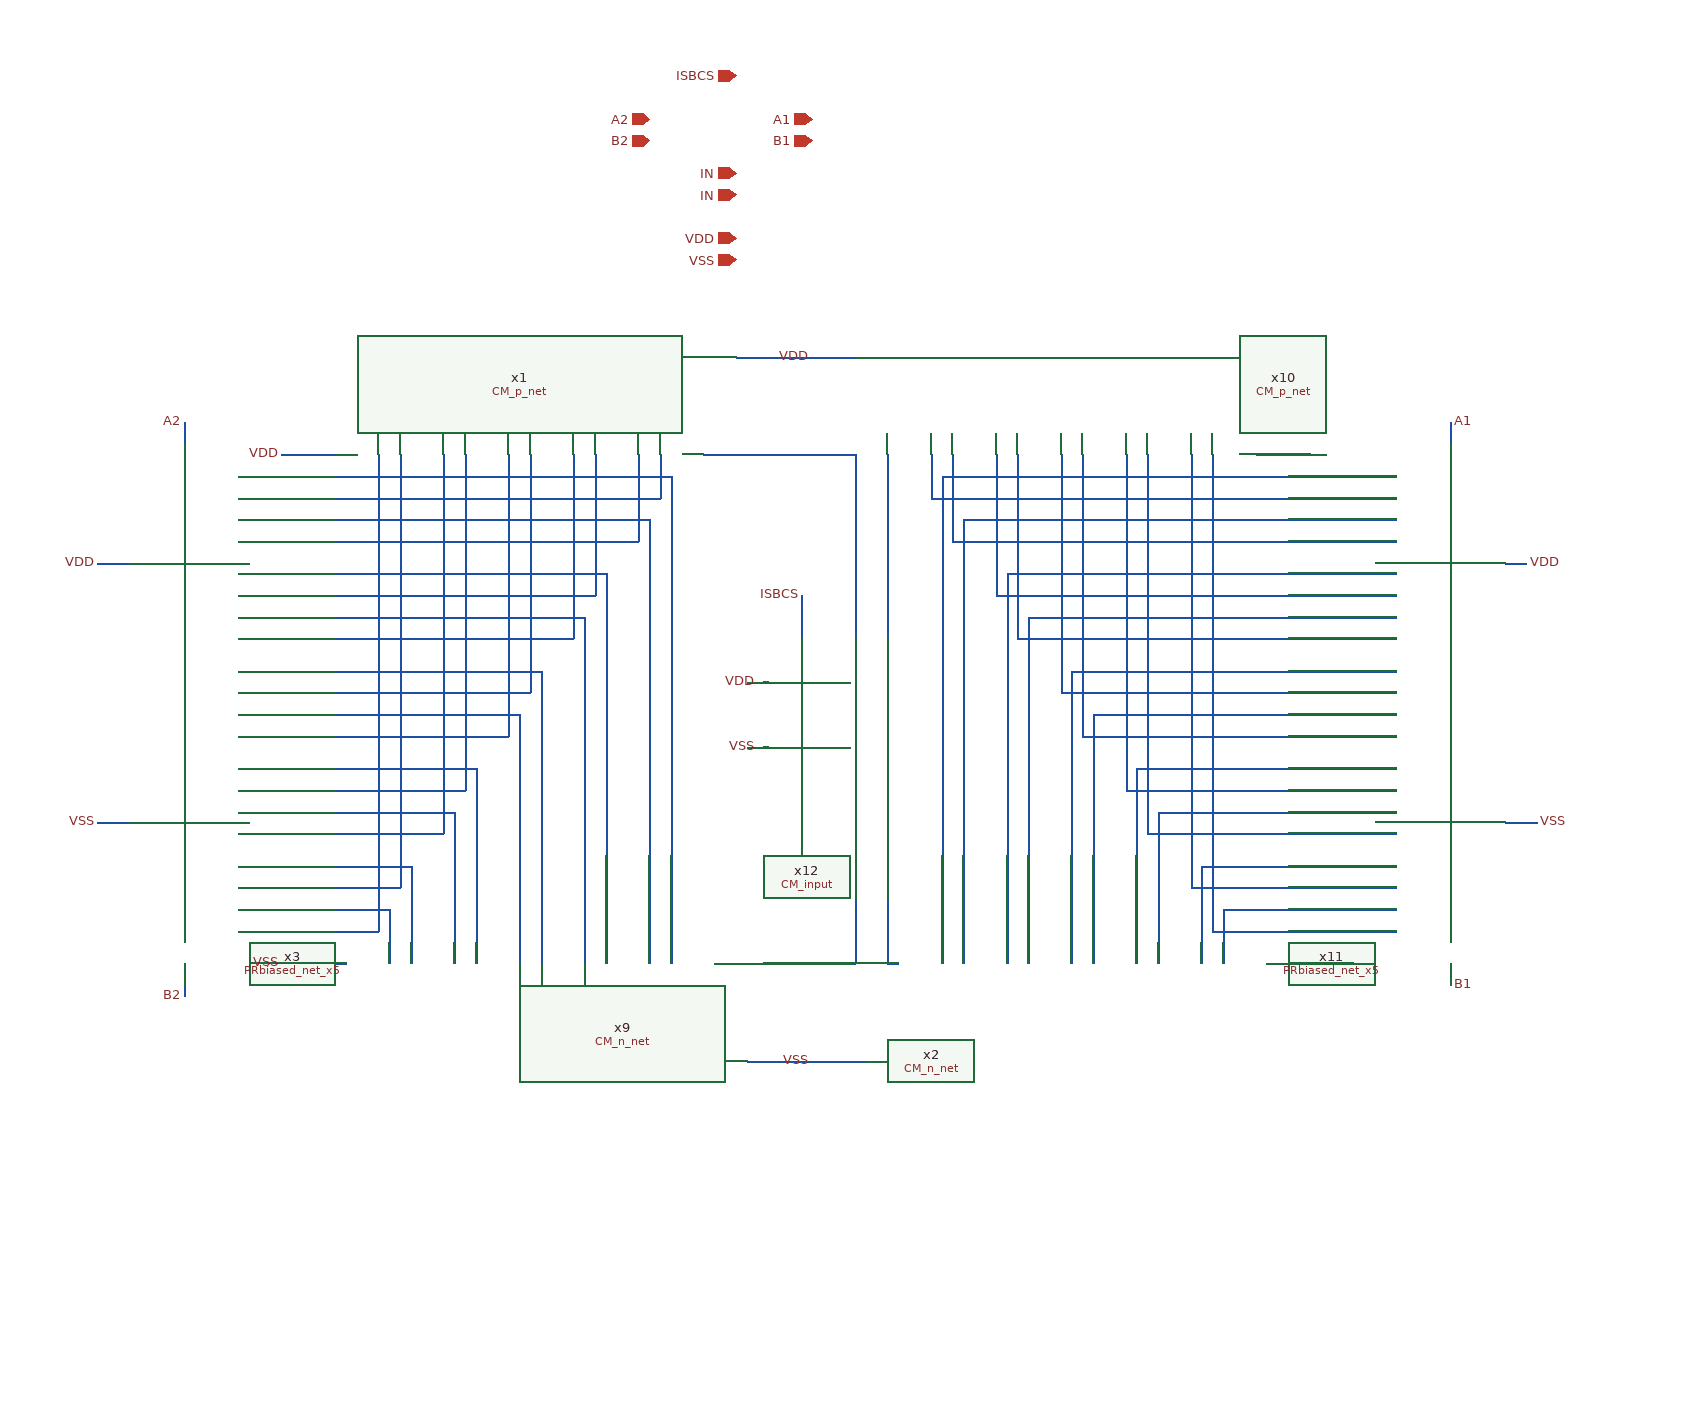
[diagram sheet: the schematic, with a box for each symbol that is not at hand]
v {xschem version=3.4.5 file_version=1.2
}
G {}
K {}
V {}
S {}
E {}
N 380 -390 380 -370 {
lab=#net1}
N 380 -310 380 -230 {
lab=#net1}
N 380 -560 380 -530 {
lab=#net2}
N 380 -700 380 -620 {
lab=#net2}
N 380 -230 390 -230 {
lab=#net1}
N 430 -680 850 -680 {
lab=#net3}
N 450 -640 850 -640 {
lab=#net4}
N 490 -590 850 -590 {
lab=#net5}
N 490 -590 490 -230 {
lab=#net5}
N 550 -500 850 -500 {
lab=#net6}
N 550 -500 550 -230 {
lab=#net6}
N 570 -460 570 -230 {
lab=#net7}
N 570 -460 850 -460 {
lab=#net7}
N 610 -410 850 -410 {
lab=#net8}
N 610 -410 610 -230 {
lab=#net8}
N 630 -370 850 -370 {
lab=#net9}
N 630 -370 630 -230 {
lab=#net9}
N 670 -320 670 -230 {
lab=#net10}
N 670 -320 850 -320 {
lab=#net10}
N 690 -280 850 -280 {
lab=#net11}
N 690 -280 690 -230 {
lab=#net11}
N 510 -550 850 -550 {
lab=#net12}
N 510 -520 510 -230 {
lab=#net12}
N 420 -660 850 -660 {
lab=#net13}
N 420 -700 420 -660 {
lab=#net13}
N 440 -620 850 -620 {
lab=#net14}
N 440 -700 440 -620 {
lab=#net14}
N 480 -570 850 -570 {
lab=#net15}
N 480 -700 480 -570 {
lab=#net15}
N 500 -530 850 -530 {
lab=#net16}
N 500 -700 500 -530 {
lab=#net16}
N 540 -480 850 -480 {
lab=#net17}
N 540 -700 540 -480 {
lab=#net17}
N 560 -440 850 -440 {
lab=#net18}
N 560 -700 560 -440 {
lab=#net18}
N 600 -390 850 -390 {
lab=#net19}
N 600 -700 600 -390 {
lab=#net19}
N 620 -350 850 -350 {
lab=#net20}
N 620 -700 620 -350 {
lab=#net20}
N 660 -300 850 -300 {
lab=#net21}
N 660 -700 660 -300 {
lab=#net21}
N 680 -260 850 -260 {
lab=#net22}
N 680 -700 680 -260 {
lab=#net22}
N 430 -680 430 -300 {
lab=#net3}
N 450 -640 450 -300 {
lab=#net4}
N 730 -230 810 -230 {
lab=#net23}
N 720 -700 770 -700 {
lab=#net24}
N 510 -550 510 -520 {
lab=#net12}
N 430 -300 430 -230 {
lab=#net3}
N 450 -300 450 -230 {
lab=#net4}
N 380 -370 380 -310 {
lab=#net1}
N 380 -620 380 -560 {
lab=#net2}
N 210 -700 350 -700 {
lab=#net25}
N 350 -700 350 -530 {
lab=#net25}
N 220 -230 350 -230 {
lab=#net26}
N 350 -390 350 -230 {
lab=#net26}
N 250 -140 360 -140 {
lab=VSS}
N 240 -790 350 -790 {
lab=VDD}
N -180 -230 -120 -230 {
lab=VSS}
N 180 -680 180 -230 {
lab=#net27}
N 160 -640 160 -230 {
lab=#net28}
N -220 -640 160 -640 {
lab=#net28}
N -220 -590 120 -590 {
lab=#net29}
N 120 -590 120 -230 {
lab=#net29}
N 100 -550 100 -230 {
lab=#net30}
N -220 -550 100 -550 {
lab=#net30}
N -220 -500 60 -500 {
lab=#net31}
N 60 -500 60 -230 {
lab=#net31}
N 40 -460 40 -230 {
lab=#net32}
N -220 -460 40 -460 {
lab=#net32}
N -220 -410 -0 -410 {
lab=#net33}
N -0 -410 -0 -230 {
lab=#net33}
N -20 -370 -20 -230 {
lab=#net34}
N -220 -370 -20 -370 {
lab=#net34}
N -220 -320 -60 -320 {
lab=#net35}
N -60 -320 -60 -230 {
lab=#net35}
N -80 -280 -80 -230 {
lab=#net36}
N -220 -280 -80 -280 {
lab=#net36}
N 170 -700 170 -660 {
lab=#net37}
N -220 -660 170 -660 {
lab=#net37}
N -220 -620 150 -620 {
lab=#net38}
N 150 -700 150 -620 {
lab=#net38}
N -220 -570 110 -570 {
lab=#net39}
N 110 -700 110 -570 {
lab=#net39}
N -220 -530 90 -530 {
lab=#net40}
N 90 -700 90 -530 {
lab=#net40}
N -220 -480 50 -480 {
lab=#net41}
N 50 -700 50 -480 {
lab=#net41}
N 30 -700 30 -440 {
lab=#net42}
N -220 -440 30 -440 {
lab=#net42}
N -10 -700 -10 -390 {
lab=#net43}
N -220 -390 -10 -390 {
lab=#net43}
N -30 -700 -30 -350 {
lab=#net44}
N -220 -350 -30 -350 {
lab=#net44}
N -70 -700 -70 -300 {
lab=#net45}
N -220 -300 -70 -300 {
lab=#net45}
N -90 -700 -90 -260 {
lab=#net46}
N -220 -260 -90 -260 {
lab=#net46}
N 300 -570 300 -530 {
lab=ISBCS}
N 250 -490 270 -490 {
lab=VDD}
N 250 -430 270 -430 {
lab=VSS}
N -180 -700 -130 -700 {
lab=VDD}
N 950 -600 970 -600 {
lab=VDD}
N -350 -600 -320 -600 {
lab=VDD}
N -350 -360 -320 -360 {
lab=VSS}
N 950 -360 980 -360 {
lab=VSS}
N -220 -680 180 -680 {
lab=#net27}
N 900 -730 900 -710 {
lab=A1}
N 900 -230 900 -210 {
lab=B1}
N -270 -730 -270 -710 {
lab=A2}
N -270 -230 -270 -200 {
lab=A2}
C {CurrentMirrors/CM_n_net.sym} 100 120 0 0 {name=x9}
C {CurrentMirrors/CM_p_net.sym} 590 -660 0 0 {name=x10}
C {PseudoResistor/PRbiased_net_x5.sym} 860 -480 1 0 {name=x11}
C {CurrentMirrors/CM_input.sym} 370 -470 0 0 {name=x12}
C {CurrentMirrors/CM_p_net.sym} 0 -660 0 1 {name=x1}
C {CurrentMirrors/CM_n_net.sym} 510 120 0 1 {name=x2}
C {PseudoResistor/PRbiased_net_x5.sym} -230 -480 3 1 {name=x3}
C {devices/iopin.sym} 240 -1050 0 0 {name=p1 lab=ISBCS}
C {devices/iopin.sym} 160 -1010 0 0 {name=p2 lab=A2}
C {devices/iopin.sym} 160 -990 0 0 {name=p3 lab=B2}
C {devices/iopin.sym} 310 -1010 0 0 {name=p4 lab=A1}
C {devices/iopin.sym} 310 -990 0 0 {name=p5 lab=B1}
C {devices/iopin.sym} 240 -960 0 0 {name=p6 lab=IN}
C {devices/iopin.sym} 240 -940 0 0 {name=p7 lab=IN}
C {devices/iopin.sym} 240 -900 0 0 {name=p8 lab=VDD}
C {devices/iopin.sym} 240 -880 0 0 {name=p9 lab=VSS}
C {devices/lab_wire.sym} 310 -790 0 0 {name=p10 sig_type=std_logic lab=VDD}
C {devices/lab_wire.sym} 260 -490 0 0 {name=p11 sig_type=std_logic lab=VDD}
C {devices/lab_wire.sym} 970 -600 0 1 {name=p12 sig_type=std_logic lab=VDD}
C {devices/lab_wire.sym} -350 -600 0 0 {name=p13 sig_type=std_logic lab=VDD}
C {devices/lab_wire.sym} 310 -140 0 0 {name=p14 sig_type=std_logic lab=VSS}
C {devices/lab_wire.sym} -350 -360 0 0 {name=p15 sig_type=std_logic lab=VSS}
C {devices/lab_wire.sym} 980 -360 0 1 {name=p16 sig_type=std_logic lab=VSS}
C {devices/lab_wire.sym} 260 -430 0 0 {name=p17 sig_type=std_logic lab=VSS}
C {devices/lab_wire.sym} -180 -700 0 0 {name=p18 sig_type=std_logic lab=VDD}
C {devices/lab_wire.sym} -180 -230 0 0 {name=p19 sig_type=std_logic lab=VSS}
C {devices/lab_wire.sym} 300 -570 0 0 {name=p20 sig_type=std_logic lab=ISBCS}
C {devices/lab_wire.sym} 900 -730 0 1 {name=p21 sig_type=std_logic lab=A1}
C {devices/lab_wire.sym} 900 -210 2 0 {name=p22 sig_type=std_logic lab=B1}
C {devices/lab_wire.sym} -270 -730 0 0 {name=p23 sig_type=std_logic lab=A2}
C {devices/lab_wire.sym} -270 -200 2 1 {name=p24 sig_type=std_logic lab=B2}
